VERSION 5.7 ;
BUSBITCHARS "[]" ;
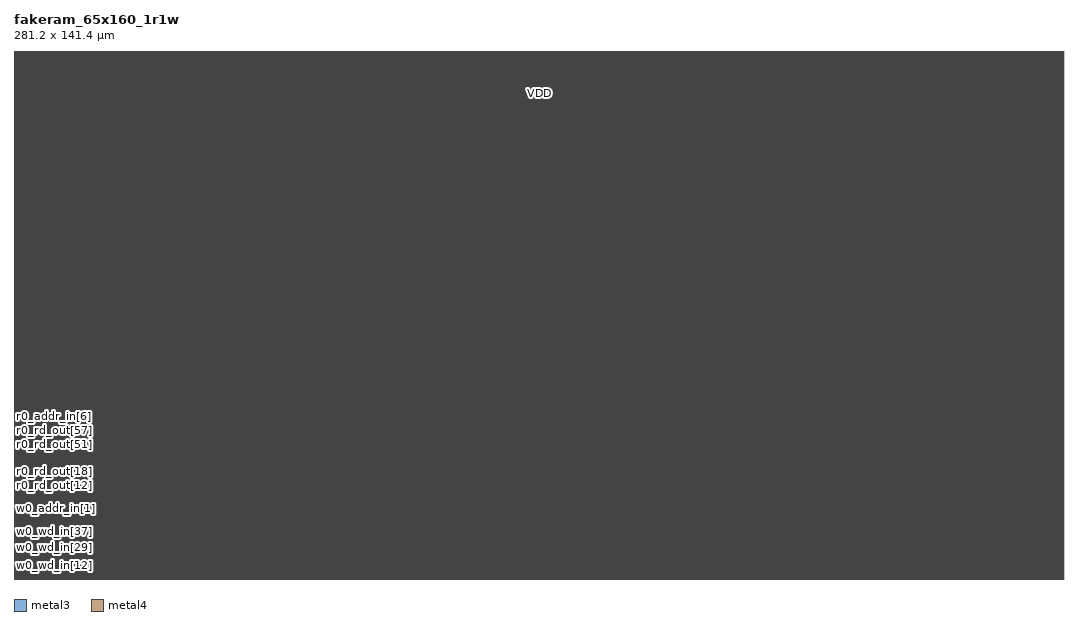
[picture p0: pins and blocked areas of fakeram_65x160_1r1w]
MACRO fakeram_65x160_1r1w
  FOREIGN fakeram_65x160_1r1w 0 0 ;
  SYMMETRY X Y R90 ;
  SIZE 281.200 BY 141.400 ;
  CLASS BLOCK ;
  PIN w0_wd_in[0]
    DIRECTION INPUT ;
    USE SIGNAL ;
    SHAPE ABUTMENT ;
    PORT
      LAYER metal3 ;
      RECT 0.000 0.280 0.140 0.420 ;
    END
  END w0_wd_in[0]
  PIN w0_wd_in[1]
    DIRECTION INPUT ;
    USE SIGNAL ;
    SHAPE ABUTMENT ;
    PORT
      LAYER metal3 ;
      RECT 0.000 0.560 0.140 0.700 ;
    END
  END w0_wd_in[1]
  PIN w0_wd_in[2]
    DIRECTION INPUT ;
    USE SIGNAL ;
    SHAPE ABUTMENT ;
    PORT
      LAYER metal3 ;
      RECT 0.000 0.840 0.140 0.980 ;
    END
  END w0_wd_in[2]
  PIN w0_wd_in[3]
    DIRECTION INPUT ;
    USE SIGNAL ;
    SHAPE ABUTMENT ;
    PORT
      LAYER metal3 ;
      RECT 0.000 1.120 0.140 1.260 ;
    END
  END w0_wd_in[3]
  PIN w0_wd_in[4]
    DIRECTION INPUT ;
    USE SIGNAL ;
    SHAPE ABUTMENT ;
    PORT
      LAYER metal3 ;
      RECT 0.000 1.400 0.140 1.540 ;
    END
  END w0_wd_in[4]
  PIN w0_wd_in[5]
    DIRECTION INPUT ;
    USE SIGNAL ;
    SHAPE ABUTMENT ;
    PORT
      LAYER metal3 ;
      RECT 0.000 1.680 0.140 1.820 ;
    END
  END w0_wd_in[5]
  PIN w0_wd_in[6]
    DIRECTION INPUT ;
    USE SIGNAL ;
    SHAPE ABUTMENT ;
    PORT
      LAYER metal3 ;
      RECT 0.000 1.960 0.140 2.100 ;
    END
  END w0_wd_in[6]
  PIN w0_wd_in[7]
    DIRECTION INPUT ;
    USE SIGNAL ;
    SHAPE ABUTMENT ;
    PORT
      LAYER metal3 ;
      RECT 0.000 2.240 0.140 2.380 ;
    END
  END w0_wd_in[7]
  PIN w0_wd_in[8]
    DIRECTION INPUT ;
    USE SIGNAL ;
    SHAPE ABUTMENT ;
    PORT
      LAYER metal3 ;
      RECT 0.000 2.520 0.140 2.660 ;
    END
  END w0_wd_in[8]
  PIN w0_wd_in[9]
    DIRECTION INPUT ;
    USE SIGNAL ;
    SHAPE ABUTMENT ;
    PORT
      LAYER metal3 ;
      RECT 0.000 2.800 0.140 2.940 ;
    END
  END w0_wd_in[9]
  PIN w0_wd_in[10]
    DIRECTION INPUT ;
    USE SIGNAL ;
    SHAPE ABUTMENT ;
    PORT
      LAYER metal3 ;
      RECT 0.000 3.080 0.140 3.220 ;
    END
  END w0_wd_in[10]
  PIN w0_wd_in[11]
    DIRECTION INPUT ;
    USE SIGNAL ;
    SHAPE ABUTMENT ;
    PORT
      LAYER metal3 ;
      RECT 0.000 3.360 0.140 3.500 ;
    END
  END w0_wd_in[11]
  PIN w0_wd_in[12]
    DIRECTION INPUT ;
    USE SIGNAL ;
    SHAPE ABUTMENT ;
    PORT
      LAYER metal3 ;
      RECT 0.000 3.640 0.140 3.780 ;
    END
  END w0_wd_in[12]
  PIN w0_wd_in[13]
    DIRECTION INPUT ;
    USE SIGNAL ;
    SHAPE ABUTMENT ;
    PORT
      LAYER metal3 ;
      RECT 0.000 3.920 0.140 4.060 ;
    END
  END w0_wd_in[13]
  PIN w0_wd_in[14]
    DIRECTION INPUT ;
    USE SIGNAL ;
    SHAPE ABUTMENT ;
    PORT
      LAYER metal3 ;
      RECT 0.000 4.200 0.140 4.340 ;
    END
  END w0_wd_in[14]
  PIN w0_wd_in[15]
    DIRECTION INPUT ;
    USE SIGNAL ;
    SHAPE ABUTMENT ;
    PORT
      LAYER metal3 ;
      RECT 0.000 4.480 0.140 4.620 ;
    END
  END w0_wd_in[15]
  PIN w0_wd_in[16]
    DIRECTION INPUT ;
    USE SIGNAL ;
    SHAPE ABUTMENT ;
    PORT
      LAYER metal3 ;
      RECT 0.000 4.760 0.140 4.900 ;
    END
  END w0_wd_in[16]
  PIN w0_wd_in[17]
    DIRECTION INPUT ;
    USE SIGNAL ;
    SHAPE ABUTMENT ;
    PORT
      LAYER metal3 ;
      RECT 0.000 5.040 0.140 5.180 ;
    END
  END w0_wd_in[17]
  PIN w0_wd_in[18]
    DIRECTION INPUT ;
    USE SIGNAL ;
    SHAPE ABUTMENT ;
    PORT
      LAYER metal3 ;
      RECT 0.000 5.320 0.140 5.460 ;
    END
  END w0_wd_in[18]
  PIN w0_wd_in[19]
    DIRECTION INPUT ;
    USE SIGNAL ;
    SHAPE ABUTMENT ;
    PORT
      LAYER metal3 ;
      RECT 0.000 5.600 0.140 5.740 ;
    END
  END w0_wd_in[19]
  PIN w0_wd_in[20]
    DIRECTION INPUT ;
    USE SIGNAL ;
    SHAPE ABUTMENT ;
    PORT
      LAYER metal3 ;
      RECT 0.000 5.880 0.140 6.020 ;
    END
  END w0_wd_in[20]
  PIN w0_wd_in[21]
    DIRECTION INPUT ;
    USE SIGNAL ;
    SHAPE ABUTMENT ;
    PORT
      LAYER metal3 ;
      RECT 0.000 6.160 0.140 6.300 ;
    END
  END w0_wd_in[21]
  PIN w0_wd_in[22]
    DIRECTION INPUT ;
    USE SIGNAL ;
    SHAPE ABUTMENT ;
    PORT
      LAYER metal3 ;
      RECT 0.000 6.440 0.140 6.580 ;
    END
  END w0_wd_in[22]
  PIN w0_wd_in[23]
    DIRECTION INPUT ;
    USE SIGNAL ;
    SHAPE ABUTMENT ;
    PORT
      LAYER metal3 ;
      RECT 0.000 6.720 0.140 6.860 ;
    END
  END w0_wd_in[23]
  PIN w0_wd_in[24]
    DIRECTION INPUT ;
    USE SIGNAL ;
    SHAPE ABUTMENT ;
    PORT
      LAYER metal3 ;
      RECT 0.000 7.000 0.140 7.140 ;
    END
  END w0_wd_in[24]
  PIN w0_wd_in[25]
    DIRECTION INPUT ;
    USE SIGNAL ;
    SHAPE ABUTMENT ;
    PORT
      LAYER metal3 ;
      RECT 0.000 7.280 0.140 7.420 ;
    END
  END w0_wd_in[25]
  PIN w0_wd_in[26]
    DIRECTION INPUT ;
    USE SIGNAL ;
    SHAPE ABUTMENT ;
    PORT
      LAYER metal3 ;
      RECT 0.000 7.560 0.140 7.700 ;
    END
  END w0_wd_in[26]
  PIN w0_wd_in[27]
    DIRECTION INPUT ;
    USE SIGNAL ;
    SHAPE ABUTMENT ;
    PORT
      LAYER metal3 ;
      RECT 0.000 7.840 0.140 7.980 ;
    END
  END w0_wd_in[27]
  PIN w0_wd_in[28]
    DIRECTION INPUT ;
    USE SIGNAL ;
    SHAPE ABUTMENT ;
    PORT
      LAYER metal3 ;
      RECT 0.000 8.120 0.140 8.260 ;
    END
  END w0_wd_in[28]
  PIN w0_wd_in[29]
    DIRECTION INPUT ;
    USE SIGNAL ;
    SHAPE ABUTMENT ;
    PORT
      LAYER metal3 ;
      RECT 0.000 8.400 0.140 8.540 ;
    END
  END w0_wd_in[29]
  PIN w0_wd_in[30]
    DIRECTION INPUT ;
    USE SIGNAL ;
    SHAPE ABUTMENT ;
    PORT
      LAYER metal3 ;
      RECT 0.000 8.680 0.140 8.820 ;
    END
  END w0_wd_in[30]
  PIN w0_wd_in[31]
    DIRECTION INPUT ;
    USE SIGNAL ;
    SHAPE ABUTMENT ;
    PORT
      LAYER metal3 ;
      RECT 0.000 8.960 0.140 9.100 ;
    END
  END w0_wd_in[31]
  PIN w0_wd_in[32]
    DIRECTION INPUT ;
    USE SIGNAL ;
    SHAPE ABUTMENT ;
    PORT
      LAYER metal3 ;
      RECT 0.000 9.240 0.140 9.380 ;
    END
  END w0_wd_in[32]
  PIN w0_wd_in[33]
    DIRECTION INPUT ;
    USE SIGNAL ;
    SHAPE ABUTMENT ;
    PORT
      LAYER metal3 ;
      RECT 0.000 9.520 0.140 9.660 ;
    END
  END w0_wd_in[33]
  PIN w0_wd_in[34]
    DIRECTION INPUT ;
    USE SIGNAL ;
    SHAPE ABUTMENT ;
    PORT
      LAYER metal3 ;
      RECT 0.000 9.800 0.140 9.940 ;
    END
  END w0_wd_in[34]
  PIN w0_wd_in[35]
    DIRECTION INPUT ;
    USE SIGNAL ;
    SHAPE ABUTMENT ;
    PORT
      LAYER metal3 ;
      RECT 0.000 10.080 0.140 10.220 ;
    END
  END w0_wd_in[35]
  PIN w0_wd_in[36]
    DIRECTION INPUT ;
    USE SIGNAL ;
    SHAPE ABUTMENT ;
    PORT
      LAYER metal3 ;
      RECT 0.000 10.360 0.140 10.500 ;
    END
  END w0_wd_in[36]
  PIN w0_wd_in[37]
    DIRECTION INPUT ;
    USE SIGNAL ;
    SHAPE ABUTMENT ;
    PORT
      LAYER metal3 ;
      RECT 0.000 10.640 0.140 10.780 ;
    END
  END w0_wd_in[37]
  PIN w0_wd_in[38]
    DIRECTION INPUT ;
    USE SIGNAL ;
    SHAPE ABUTMENT ;
    PORT
      LAYER metal3 ;
      RECT 0.000 10.920 0.140 11.060 ;
    END
  END w0_wd_in[38]
  PIN w0_wd_in[39]
    DIRECTION INPUT ;
    USE SIGNAL ;
    SHAPE ABUTMENT ;
    PORT
      LAYER metal3 ;
      RECT 0.000 11.200 0.140 11.340 ;
    END
  END w0_wd_in[39]
  PIN w0_wd_in[40]
    DIRECTION INPUT ;
    USE SIGNAL ;
    SHAPE ABUTMENT ;
    PORT
      LAYER metal3 ;
      RECT 0.000 11.480 0.140 11.620 ;
    END
  END w0_wd_in[40]
  PIN w0_wd_in[41]
    DIRECTION INPUT ;
    USE SIGNAL ;
    SHAPE ABUTMENT ;
    PORT
      LAYER metal3 ;
      RECT 0.000 11.760 0.140 11.900 ;
    END
  END w0_wd_in[41]
  PIN w0_wd_in[42]
    DIRECTION INPUT ;
    USE SIGNAL ;
    SHAPE ABUTMENT ;
    PORT
      LAYER metal3 ;
      RECT 0.000 12.040 0.140 12.180 ;
    END
  END w0_wd_in[42]
  PIN w0_wd_in[43]
    DIRECTION INPUT ;
    USE SIGNAL ;
    SHAPE ABUTMENT ;
    PORT
      LAYER metal3 ;
      RECT 0.000 12.320 0.140 12.460 ;
    END
  END w0_wd_in[43]
  PIN w0_wd_in[44]
    DIRECTION INPUT ;
    USE SIGNAL ;
    SHAPE ABUTMENT ;
    PORT
      LAYER metal3 ;
      RECT 0.000 12.600 0.140 12.740 ;
    END
  END w0_wd_in[44]
  PIN w0_wd_in[45]
    DIRECTION INPUT ;
    USE SIGNAL ;
    SHAPE ABUTMENT ;
    PORT
      LAYER metal3 ;
      RECT 0.000 12.880 0.140 13.020 ;
    END
  END w0_wd_in[45]
  PIN w0_wd_in[46]
    DIRECTION INPUT ;
    USE SIGNAL ;
    SHAPE ABUTMENT ;
    PORT
      LAYER metal3 ;
      RECT 0.000 13.160 0.140 13.300 ;
    END
  END w0_wd_in[46]
  PIN w0_wd_in[47]
    DIRECTION INPUT ;
    USE SIGNAL ;
    SHAPE ABUTMENT ;
    PORT
      LAYER metal3 ;
      RECT 0.000 13.440 0.140 13.580 ;
    END
  END w0_wd_in[47]
  PIN w0_wd_in[48]
    DIRECTION INPUT ;
    USE SIGNAL ;
    SHAPE ABUTMENT ;
    PORT
      LAYER metal3 ;
      RECT 0.000 13.720 0.140 13.860 ;
    END
  END w0_wd_in[48]
  PIN w0_wd_in[49]
    DIRECTION INPUT ;
    USE SIGNAL ;
    SHAPE ABUTMENT ;
    PORT
      LAYER metal3 ;
      RECT 0.000 14.000 0.140 14.140 ;
    END
  END w0_wd_in[49]
  PIN w0_wd_in[50]
    DIRECTION INPUT ;
    USE SIGNAL ;
    SHAPE ABUTMENT ;
    PORT
      LAYER metal3 ;
      RECT 0.000 14.280 0.140 14.420 ;
    END
  END w0_wd_in[50]
  PIN w0_wd_in[51]
    DIRECTION INPUT ;
    USE SIGNAL ;
    SHAPE ABUTMENT ;
    PORT
      LAYER metal3 ;
      RECT 0.000 14.560 0.140 14.700 ;
    END
  END w0_wd_in[51]
  PIN w0_wd_in[52]
    DIRECTION INPUT ;
    USE SIGNAL ;
    SHAPE ABUTMENT ;
    PORT
      LAYER metal3 ;
      RECT 0.000 14.840 0.140 14.980 ;
    END
  END w0_wd_in[52]
  PIN w0_wd_in[53]
    DIRECTION INPUT ;
    USE SIGNAL ;
    SHAPE ABUTMENT ;
    PORT
      LAYER metal3 ;
      RECT 0.000 15.120 0.140 15.260 ;
    END
  END w0_wd_in[53]
  PIN w0_wd_in[54]
    DIRECTION INPUT ;
    USE SIGNAL ;
    SHAPE ABUTMENT ;
    PORT
      LAYER metal3 ;
      RECT 0.000 15.400 0.140 15.540 ;
    END
  END w0_wd_in[54]
  PIN w0_wd_in[55]
    DIRECTION INPUT ;
    USE SIGNAL ;
    SHAPE ABUTMENT ;
    PORT
      LAYER metal3 ;
      RECT 0.000 15.680 0.140 15.820 ;
    END
  END w0_wd_in[55]
  PIN w0_wd_in[56]
    DIRECTION INPUT ;
    USE SIGNAL ;
    SHAPE ABUTMENT ;
    PORT
      LAYER metal3 ;
      RECT 0.000 15.960 0.140 16.100 ;
    END
  END w0_wd_in[56]
  PIN w0_wd_in[57]
    DIRECTION INPUT ;
    USE SIGNAL ;
    SHAPE ABUTMENT ;
    PORT
      LAYER metal3 ;
      RECT 0.000 16.240 0.140 16.380 ;
    END
  END w0_wd_in[57]
  PIN w0_wd_in[58]
    DIRECTION INPUT ;
    USE SIGNAL ;
    SHAPE ABUTMENT ;
    PORT
      LAYER metal3 ;
      RECT 0.000 16.520 0.140 16.660 ;
    END
  END w0_wd_in[58]
  PIN w0_wd_in[59]
    DIRECTION INPUT ;
    USE SIGNAL ;
    SHAPE ABUTMENT ;
    PORT
      LAYER metal3 ;
      RECT 0.000 16.800 0.140 16.940 ;
    END
  END w0_wd_in[59]
  PIN w0_wd_in[60]
    DIRECTION INPUT ;
    USE SIGNAL ;
    SHAPE ABUTMENT ;
    PORT
      LAYER metal3 ;
      RECT 0.000 17.080 0.140 17.220 ;
    END
  END w0_wd_in[60]
  PIN w0_wd_in[61]
    DIRECTION INPUT ;
    USE SIGNAL ;
    SHAPE ABUTMENT ;
    PORT
      LAYER metal3 ;
      RECT 0.000 17.360 0.140 17.500 ;
    END
  END w0_wd_in[61]
  PIN w0_wd_in[62]
    DIRECTION INPUT ;
    USE SIGNAL ;
    SHAPE ABUTMENT ;
    PORT
      LAYER metal3 ;
      RECT 0.000 17.640 0.140 17.780 ;
    END
  END w0_wd_in[62]
  PIN w0_wd_in[63]
    DIRECTION INPUT ;
    USE SIGNAL ;
    SHAPE ABUTMENT ;
    PORT
      LAYER metal3 ;
      RECT 0.000 17.920 0.140 18.060 ;
    END
  END w0_wd_in[63]
  PIN w0_wd_in[64]
    DIRECTION INPUT ;
    USE SIGNAL ;
    SHAPE ABUTMENT ;
    PORT
      LAYER metal3 ;
      RECT 0.000 18.200 0.140 18.340 ;
    END
  END w0_wd_in[64]
  PIN w0_addr_in[0]
    DIRECTION INPUT ;
    USE SIGNAL ;
    SHAPE ABUTMENT ;
    PORT
      LAYER metal3 ;
      RECT 0.000 18.480 0.140 18.620 ;
    END
  END w0_addr_in[0]
  PIN w0_addr_in[1]
    DIRECTION INPUT ;
    USE SIGNAL ;
    SHAPE ABUTMENT ;
    PORT
      LAYER metal3 ;
      RECT 0.000 18.760 0.140 18.900 ;
    END
  END w0_addr_in[1]
  PIN w0_addr_in[2]
    DIRECTION INPUT ;
    USE SIGNAL ;
    SHAPE ABUTMENT ;
    PORT
      LAYER metal3 ;
      RECT 0.000 19.040 0.140 19.180 ;
    END
  END w0_addr_in[2]
  PIN w0_addr_in[3]
    DIRECTION INPUT ;
    USE SIGNAL ;
    SHAPE ABUTMENT ;
    PORT
      LAYER metal3 ;
      RECT 0.000 19.320 0.140 19.460 ;
    END
  END w0_addr_in[3]
  PIN w0_addr_in[4]
    DIRECTION INPUT ;
    USE SIGNAL ;
    SHAPE ABUTMENT ;
    PORT
      LAYER metal3 ;
      RECT 0.000 19.600 0.140 19.740 ;
    END
  END w0_addr_in[4]
  PIN w0_addr_in[5]
    DIRECTION INPUT ;
    USE SIGNAL ;
    SHAPE ABUTMENT ;
    PORT
      LAYER metal3 ;
      RECT 0.000 19.880 0.140 20.020 ;
    END
  END w0_addr_in[5]
  PIN w0_addr_in[6]
    DIRECTION INPUT ;
    USE SIGNAL ;
    SHAPE ABUTMENT ;
    PORT
      LAYER metal3 ;
      RECT 0.000 20.160 0.140 20.300 ;
    END
  END w0_addr_in[6]
  PIN w0_addr_in[7]
    DIRECTION INPUT ;
    USE SIGNAL ;
    SHAPE ABUTMENT ;
    PORT
      LAYER metal3 ;
      RECT 0.000 20.440 0.140 20.580 ;
    END
  END w0_addr_in[7]
  PIN w0_clk
    DIRECTION INPUT ;
    USE SIGNAL ;
    SHAPE ABUTMENT ;
    PORT
      LAYER metal3 ;
      RECT 0.000 20.720 0.140 20.860 ;
    END
  END w0_clk
  PIN w0_ce_in
    DIRECTION INPUT ;
    USE SIGNAL ;
    SHAPE ABUTMENT ;
    PORT
      LAYER metal3 ;
      RECT 0.000 21.000 0.140 21.140 ;
    END
  END w0_ce_in
  PIN w0_we_in
    DIRECTION INPUT ;
    USE SIGNAL ;
    SHAPE ABUTMENT ;
    PORT
      LAYER metal3 ;
      RECT 0.000 21.280 0.140 21.420 ;
    END
  END w0_we_in
  PIN r0_rd_out[0]
    DIRECTION OUTPUT ;
    USE SIGNAL ;
    SHAPE ABUTMENT ;
    PORT
      LAYER metal3 ;
      RECT 0.000 21.560 0.140 21.700 ;
    END
  END r0_rd_out[0]
  PIN r0_rd_out[1]
    DIRECTION OUTPUT ;
    USE SIGNAL ;
    SHAPE ABUTMENT ;
    PORT
      LAYER metal3 ;
      RECT 0.000 21.840 0.140 21.980 ;
    END
  END r0_rd_out[1]
  PIN r0_rd_out[2]
    DIRECTION OUTPUT ;
    USE SIGNAL ;
    SHAPE ABUTMENT ;
    PORT
      LAYER metal3 ;
      RECT 0.000 22.120 0.140 22.260 ;
    END
  END r0_rd_out[2]
  PIN r0_rd_out[3]
    DIRECTION OUTPUT ;
    USE SIGNAL ;
    SHAPE ABUTMENT ;
    PORT
      LAYER metal3 ;
      RECT 0.000 22.400 0.140 22.540 ;
    END
  END r0_rd_out[3]
  PIN r0_rd_out[4]
    DIRECTION OUTPUT ;
    USE SIGNAL ;
    SHAPE ABUTMENT ;
    PORT
      LAYER metal3 ;
      RECT 0.000 22.680 0.140 22.820 ;
    END
  END r0_rd_out[4]
  PIN r0_rd_out[5]
    DIRECTION OUTPUT ;
    USE SIGNAL ;
    SHAPE ABUTMENT ;
    PORT
      LAYER metal3 ;
      RECT 0.000 22.960 0.140 23.100 ;
    END
  END r0_rd_out[5]
  PIN r0_rd_out[6]
    DIRECTION OUTPUT ;
    USE SIGNAL ;
    SHAPE ABUTMENT ;
    PORT
      LAYER metal3 ;
      RECT 0.000 23.240 0.140 23.380 ;
    END
  END r0_rd_out[6]
  PIN r0_rd_out[7]
    DIRECTION OUTPUT ;
    USE SIGNAL ;
    SHAPE ABUTMENT ;
    PORT
      LAYER metal3 ;
      RECT 0.000 23.520 0.140 23.660 ;
    END
  END r0_rd_out[7]
  PIN r0_rd_out[8]
    DIRECTION OUTPUT ;
    USE SIGNAL ;
    SHAPE ABUTMENT ;
    PORT
      LAYER metal3 ;
      RECT 0.000 23.800 0.140 23.940 ;
    END
  END r0_rd_out[8]
  PIN r0_rd_out[9]
    DIRECTION OUTPUT ;
    USE SIGNAL ;
    SHAPE ABUTMENT ;
    PORT
      LAYER metal3 ;
      RECT 0.000 24.080 0.140 24.220 ;
    END
  END r0_rd_out[9]
  PIN r0_rd_out[10]
    DIRECTION OUTPUT ;
    USE SIGNAL ;
    SHAPE ABUTMENT ;
    PORT
      LAYER metal3 ;
      RECT 0.000 24.360 0.140 24.500 ;
    END
  END r0_rd_out[10]
  PIN r0_rd_out[11]
    DIRECTION OUTPUT ;
    USE SIGNAL ;
    SHAPE ABUTMENT ;
    PORT
      LAYER metal3 ;
      RECT 0.000 24.640 0.140 24.780 ;
    END
  END r0_rd_out[11]
  PIN r0_rd_out[12]
    DIRECTION OUTPUT ;
    USE SIGNAL ;
    SHAPE ABUTMENT ;
    PORT
      LAYER metal3 ;
      RECT 0.000 24.920 0.140 25.060 ;
    END
  END r0_rd_out[12]
  PIN r0_rd_out[13]
    DIRECTION OUTPUT ;
    USE SIGNAL ;
    SHAPE ABUTMENT ;
    PORT
      LAYER metal3 ;
      RECT 0.000 25.200 0.140 25.340 ;
    END
  END r0_rd_out[13]
  PIN r0_rd_out[14]
    DIRECTION OUTPUT ;
    USE SIGNAL ;
    SHAPE ABUTMENT ;
    PORT
      LAYER metal3 ;
      RECT 0.000 25.480 0.140 25.620 ;
    END
  END r0_rd_out[14]
  PIN r0_rd_out[15]
    DIRECTION OUTPUT ;
    USE SIGNAL ;
    SHAPE ABUTMENT ;
    PORT
      LAYER metal3 ;
      RECT 0.000 25.760 0.140 25.900 ;
    END
  END r0_rd_out[15]
  PIN r0_rd_out[16]
    DIRECTION OUTPUT ;
    USE SIGNAL ;
    SHAPE ABUTMENT ;
    PORT
      LAYER metal3 ;
      RECT 0.000 26.040 0.140 26.180 ;
    END
  END r0_rd_out[16]
  PIN r0_rd_out[17]
    DIRECTION OUTPUT ;
    USE SIGNAL ;
    SHAPE ABUTMENT ;
    PORT
      LAYER metal3 ;
      RECT 0.000 26.320 0.140 26.460 ;
    END
  END r0_rd_out[17]
  PIN r0_rd_out[18]
    DIRECTION OUTPUT ;
    USE SIGNAL ;
    SHAPE ABUTMENT ;
    PORT
      LAYER metal3 ;
      RECT 0.000 26.600 0.140 26.740 ;
    END
  END r0_rd_out[18]
  PIN r0_rd_out[19]
    DIRECTION OUTPUT ;
    USE SIGNAL ;
    SHAPE ABUTMENT ;
    PORT
      LAYER metal3 ;
      RECT 0.000 26.880 0.140 27.020 ;
    END
  END r0_rd_out[19]
  PIN r0_rd_out[20]
    DIRECTION OUTPUT ;
    USE SIGNAL ;
    SHAPE ABUTMENT ;
    PORT
      LAYER metal3 ;
      RECT 0.000 27.160 0.140 27.300 ;
    END
  END r0_rd_out[20]
  PIN r0_rd_out[21]
    DIRECTION OUTPUT ;
    USE SIGNAL ;
    SHAPE ABUTMENT ;
    PORT
      LAYER metal3 ;
      RECT 0.000 27.440 0.140 27.580 ;
    END
  END r0_rd_out[21]
  PIN r0_rd_out[22]
    DIRECTION OUTPUT ;
    USE SIGNAL ;
    SHAPE ABUTMENT ;
    PORT
      LAYER metal3 ;
      RECT 0.000 27.720 0.140 27.860 ;
    END
  END r0_rd_out[22]
  PIN r0_rd_out[23]
    DIRECTION OUTPUT ;
    USE SIGNAL ;
    SHAPE ABUTMENT ;
    PORT
      LAYER metal3 ;
      RECT 0.000 28.000 0.140 28.140 ;
    END
  END r0_rd_out[23]
  PIN r0_rd_out[24]
    DIRECTION OUTPUT ;
    USE SIGNAL ;
    SHAPE ABUTMENT ;
    PORT
      LAYER metal3 ;
      RECT 0.000 28.280 0.140 28.420 ;
    END
  END r0_rd_out[24]
  PIN r0_rd_out[25]
    DIRECTION OUTPUT ;
    USE SIGNAL ;
    SHAPE ABUTMENT ;
    PORT
      LAYER metal3 ;
      RECT 0.000 28.560 0.140 28.700 ;
    END
  END r0_rd_out[25]
  PIN r0_rd_out[26]
    DIRECTION OUTPUT ;
    USE SIGNAL ;
    SHAPE ABUTMENT ;
    PORT
      LAYER metal3 ;
      RECT 0.000 28.840 0.140 28.980 ;
    END
  END r0_rd_out[26]
  PIN r0_rd_out[27]
    DIRECTION OUTPUT ;
    USE SIGNAL ;
    SHAPE ABUTMENT ;
    PORT
      LAYER metal3 ;
      RECT 0.000 29.120 0.140 29.260 ;
    END
  END r0_rd_out[27]
  PIN r0_rd_out[28]
    DIRECTION OUTPUT ;
    USE SIGNAL ;
    SHAPE ABUTMENT ;
    PORT
      LAYER metal3 ;
      RECT 0.000 29.400 0.140 29.540 ;
    END
  END r0_rd_out[28]
  PIN r0_rd_out[29]
    DIRECTION OUTPUT ;
    USE SIGNAL ;
    SHAPE ABUTMENT ;
    PORT
      LAYER metal3 ;
      RECT 0.000 29.680 0.140 29.820 ;
    END
  END r0_rd_out[29]
  PIN r0_rd_out[30]
    DIRECTION OUTPUT ;
    USE SIGNAL ;
    SHAPE ABUTMENT ;
    PORT
      LAYER metal3 ;
      RECT 0.000 29.960 0.140 30.100 ;
    END
  END r0_rd_out[30]
  PIN r0_rd_out[31]
    DIRECTION OUTPUT ;
    USE SIGNAL ;
    SHAPE ABUTMENT ;
    PORT
      LAYER metal3 ;
      RECT 0.000 30.240 0.140 30.380 ;
    END
  END r0_rd_out[31]
  PIN r0_rd_out[32]
    DIRECTION OUTPUT ;
    USE SIGNAL ;
    SHAPE ABUTMENT ;
    PORT
      LAYER metal3 ;
      RECT 0.000 30.520 0.140 30.660 ;
    END
  END r0_rd_out[32]
  PIN r0_rd_out[33]
    DIRECTION OUTPUT ;
    USE SIGNAL ;
    SHAPE ABUTMENT ;
    PORT
      LAYER metal3 ;
      RECT 0.000 30.800 0.140 30.940 ;
    END
  END r0_rd_out[33]
  PIN r0_rd_out[34]
    DIRECTION OUTPUT ;
    USE SIGNAL ;
    SHAPE ABUTMENT ;
    PORT
      LAYER metal3 ;
      RECT 0.000 31.080 0.140 31.220 ;
    END
  END r0_rd_out[34]
  PIN r0_rd_out[35]
    DIRECTION OUTPUT ;
    USE SIGNAL ;
    SHAPE ABUTMENT ;
    PORT
      LAYER metal3 ;
      RECT 0.000 31.360 0.140 31.500 ;
    END
  END r0_rd_out[35]
  PIN r0_rd_out[36]
    DIRECTION OUTPUT ;
    USE SIGNAL ;
    SHAPE ABUTMENT ;
    PORT
      LAYER metal3 ;
      RECT 0.000 31.640 0.140 31.780 ;
    END
  END r0_rd_out[36]
  PIN r0_rd_out[37]
    DIRECTION OUTPUT ;
    USE SIGNAL ;
    SHAPE ABUTMENT ;
    PORT
      LAYER metal3 ;
      RECT 0.000 31.920 0.140 32.060 ;
    END
  END r0_rd_out[37]
  PIN r0_rd_out[38]
    DIRECTION OUTPUT ;
    USE SIGNAL ;
    SHAPE ABUTMENT ;
    PORT
      LAYER metal3 ;
      RECT 0.000 32.200 0.140 32.340 ;
    END
  END r0_rd_out[38]
  PIN r0_rd_out[39]
    DIRECTION OUTPUT ;
    USE SIGNAL ;
    SHAPE ABUTMENT ;
    PORT
      LAYER metal3 ;
      RECT 0.000 32.480 0.140 32.620 ;
    END
  END r0_rd_out[39]
  PIN r0_rd_out[40]
    DIRECTION OUTPUT ;
    USE SIGNAL ;
    SHAPE ABUTMENT ;
    PORT
      LAYER metal3 ;
      RECT 0.000 32.760 0.140 32.900 ;
    END
  END r0_rd_out[40]
  PIN r0_rd_out[41]
    DIRECTION OUTPUT ;
    USE SIGNAL ;
    SHAPE ABUTMENT ;
    PORT
      LAYER metal3 ;
      RECT 0.000 33.040 0.140 33.180 ;
    END
  END r0_rd_out[41]
  PIN r0_rd_out[42]
    DIRECTION OUTPUT ;
    USE SIGNAL ;
    SHAPE ABUTMENT ;
    PORT
      LAYER metal3 ;
      RECT 0.000 33.320 0.140 33.460 ;
    END
  END r0_rd_out[42]
  PIN r0_rd_out[43]
    DIRECTION OUTPUT ;
    USE SIGNAL ;
    SHAPE ABUTMENT ;
    PORT
      LAYER metal3 ;
      RECT 0.000 33.600 0.140 33.740 ;
    END
  END r0_rd_out[43]
  PIN r0_rd_out[44]
    DIRECTION OUTPUT ;
    USE SIGNAL ;
    SHAPE ABUTMENT ;
    PORT
      LAYER metal3 ;
      RECT 0.000 33.880 0.140 34.020 ;
    END
  END r0_rd_out[44]
  PIN r0_rd_out[45]
    DIRECTION OUTPUT ;
    USE SIGNAL ;
    SHAPE ABUTMENT ;
    PORT
      LAYER metal3 ;
      RECT 0.000 34.160 0.140 34.300 ;
    END
  END r0_rd_out[45]
  PIN r0_rd_out[46]
    DIRECTION OUTPUT ;
    USE SIGNAL ;
    SHAPE ABUTMENT ;
    PORT
      LAYER metal3 ;
      RECT 0.000 34.440 0.140 34.580 ;
    END
  END r0_rd_out[46]
  PIN r0_rd_out[47]
    DIRECTION OUTPUT ;
    USE SIGNAL ;
    SHAPE ABUTMENT ;
    PORT
      LAYER metal3 ;
      RECT 0.000 34.720 0.140 34.860 ;
    END
  END r0_rd_out[47]
  PIN r0_rd_out[48]
    DIRECTION OUTPUT ;
    USE SIGNAL ;
    SHAPE ABUTMENT ;
    PORT
      LAYER metal3 ;
      RECT 0.000 35.000 0.140 35.140 ;
    END
  END r0_rd_out[48]
  PIN r0_rd_out[49]
    DIRECTION OUTPUT ;
    USE SIGNAL ;
    SHAPE ABUTMENT ;
    PORT
      LAYER metal3 ;
      RECT 0.000 35.280 0.140 35.420 ;
    END
  END r0_rd_out[49]
  PIN r0_rd_out[50]
    DIRECTION OUTPUT ;
    USE SIGNAL ;
    SHAPE ABUTMENT ;
    PORT
      LAYER metal3 ;
      RECT 0.000 35.560 0.140 35.700 ;
    END
  END r0_rd_out[50]
  PIN r0_rd_out[51]
    DIRECTION OUTPUT ;
    USE SIGNAL ;
    SHAPE ABUTMENT ;
    PORT
      LAYER metal3 ;
      RECT 0.000 35.840 0.140 35.980 ;
    END
  END r0_rd_out[51]
  PIN r0_rd_out[52]
    DIRECTION OUTPUT ;
    USE SIGNAL ;
    SHAPE ABUTMENT ;
    PORT
      LAYER metal3 ;
      RECT 0.000 36.120 0.140 36.260 ;
    END
  END r0_rd_out[52]
  PIN r0_rd_out[53]
    DIRECTION OUTPUT ;
    USE SIGNAL ;
    SHAPE ABUTMENT ;
    PORT
      LAYER metal3 ;
      RECT 0.000 36.400 0.140 36.540 ;
    END
  END r0_rd_out[53]
  PIN r0_rd_out[54]
    DIRECTION OUTPUT ;
    USE SIGNAL ;
    SHAPE ABUTMENT ;
    PORT
      LAYER metal3 ;
      RECT 0.000 36.680 0.140 36.820 ;
    END
  END r0_rd_out[54]
  PIN r0_rd_out[55]
    DIRECTION OUTPUT ;
    USE SIGNAL ;
    SHAPE ABUTMENT ;
    PORT
      LAYER metal3 ;
      RECT 0.000 36.960 0.140 37.100 ;
    END
  END r0_rd_out[55]
  PIN r0_rd_out[56]
    DIRECTION OUTPUT ;
    USE SIGNAL ;
    SHAPE ABUTMENT ;
    PORT
      LAYER metal3 ;
      RECT 0.000 37.240 0.140 37.380 ;
    END
  END r0_rd_out[56]
  PIN r0_rd_out[57]
    DIRECTION OUTPUT ;
    USE SIGNAL ;
    SHAPE ABUTMENT ;
    PORT
      LAYER metal3 ;
      RECT 0.000 37.520 0.140 37.660 ;
    END
  END r0_rd_out[57]
  PIN r0_rd_out[58]
    DIRECTION OUTPUT ;
    USE SIGNAL ;
    SHAPE ABUTMENT ;
    PORT
      LAYER metal3 ;
      RECT 0.000 37.800 0.140 37.940 ;
    END
  END r0_rd_out[58]
  PIN r0_rd_out[59]
    DIRECTION OUTPUT ;
    USE SIGNAL ;
    SHAPE ABUTMENT ;
    PORT
      LAYER metal3 ;
      RECT 0.000 38.080 0.140 38.220 ;
    END
  END r0_rd_out[59]
  PIN r0_rd_out[60]
    DIRECTION OUTPUT ;
    USE SIGNAL ;
    SHAPE ABUTMENT ;
    PORT
      LAYER metal3 ;
      RECT 0.000 38.360 0.140 38.500 ;
    END
  END r0_rd_out[60]
  PIN r0_rd_out[61]
    DIRECTION OUTPUT ;
    USE SIGNAL ;
    SHAPE ABUTMENT ;
    PORT
      LAYER metal3 ;
      RECT 0.000 38.640 0.140 38.780 ;
    END
  END r0_rd_out[61]
  PIN r0_rd_out[62]
    DIRECTION OUTPUT ;
    USE SIGNAL ;
    SHAPE ABUTMENT ;
    PORT
      LAYER metal3 ;
      RECT 0.000 38.920 0.140 39.060 ;
    END
  END r0_rd_out[62]
  PIN r0_rd_out[63]
    DIRECTION OUTPUT ;
    USE SIGNAL ;
    SHAPE ABUTMENT ;
    PORT
      LAYER metal3 ;
      RECT 0.000 39.200 0.140 39.340 ;
    END
  END r0_rd_out[63]
  PIN r0_rd_out[64]
    DIRECTION OUTPUT ;
    USE SIGNAL ;
    SHAPE ABUTMENT ;
    PORT
      LAYER metal3 ;
      RECT 0.000 39.480 0.140 39.620 ;
    END
  END r0_rd_out[64]
  PIN r0_addr_in[0]
    DIRECTION INPUT ;
    USE SIGNAL ;
    SHAPE ABUTMENT ;
    PORT
      LAYER metal3 ;
      RECT 0.000 39.760 0.140 39.900 ;
    END
  END r0_addr_in[0]
  PIN r0_addr_in[1]
    DIRECTION INPUT ;
    USE SIGNAL ;
    SHAPE ABUTMENT ;
    PORT
      LAYER metal3 ;
      RECT 0.000 40.040 0.140 40.180 ;
    END
  END r0_addr_in[1]
  PIN r0_addr_in[2]
    DIRECTION INPUT ;
    USE SIGNAL ;
    SHAPE ABUTMENT ;
    PORT
      LAYER metal3 ;
      RECT 0.000 40.320 0.140 40.460 ;
    END
  END r0_addr_in[2]
  PIN r0_addr_in[3]
    DIRECTION INPUT ;
    USE SIGNAL ;
    SHAPE ABUTMENT ;
    PORT
      LAYER metal3 ;
      RECT 0.000 40.600 0.140 40.740 ;
    END
  END r0_addr_in[3]
  PIN r0_addr_in[4]
    DIRECTION INPUT ;
    USE SIGNAL ;
    SHAPE ABUTMENT ;
    PORT
      LAYER metal3 ;
      RECT 0.000 40.880 0.140 41.020 ;
    END
  END r0_addr_in[4]
  PIN r0_addr_in[5]
    DIRECTION INPUT ;
    USE SIGNAL ;
    SHAPE ABUTMENT ;
    PORT
      LAYER metal3 ;
      RECT 0.000 41.160 0.140 41.300 ;
    END
  END r0_addr_in[5]
  PIN r0_addr_in[6]
    DIRECTION INPUT ;
    USE SIGNAL ;
    SHAPE ABUTMENT ;
    PORT
      LAYER metal3 ;
      RECT 0.000 41.440 0.140 41.580 ;
    END
  END r0_addr_in[6]
  PIN r0_addr_in[7]
    DIRECTION INPUT ;
    USE SIGNAL ;
    SHAPE ABUTMENT ;
    PORT
      LAYER metal3 ;
      RECT 0.000 41.720 0.140 41.860 ;
    END
  END r0_addr_in[7]
  PIN r0_clk
    DIRECTION INPUT ;
    USE SIGNAL ;
    SHAPE ABUTMENT ;
    PORT
      LAYER metal3 ;
      RECT 0.000 42.000 0.140 42.140 ;
    END
  END r0_clk
  PIN r0_ce_in
    DIRECTION INPUT ;
    USE SIGNAL ;
    SHAPE ABUTMENT ;
    PORT
      LAYER metal3 ;
      RECT 0.000 42.280 0.140 42.420 ;
    END
  END r0_ce_in
  PIN VDD
    DIRECTION INOUT ;
    USE POWER ;
    PORT
      LAYER metal4 ;
      RECT 0.190 0.000 281.010 0.140 ;
      RECT 0.190 0.560 281.010 0.700 ;
      RECT 0.190 1.120 281.010 1.260 ;
      RECT 0.190 1.680 281.010 1.820 ;
      RECT 0.190 2.240 281.010 2.380 ;
      RECT 0.190 2.800 281.010 2.940 ;
      RECT 0.190 3.360 281.010 3.500 ;
      RECT 0.190 3.920 281.010 4.060 ;
      RECT 0.190 4.480 281.010 4.620 ;
      RECT 0.190 5.040 281.010 5.180 ;
      RECT 0.190 5.600 281.010 5.740 ;
      RECT 0.190 6.160 281.010 6.300 ;
      RECT 0.190 6.720 281.010 6.860 ;
      RECT 0.190 7.280 281.010 7.420 ;
      RECT 0.190 7.840 281.010 7.980 ;
      RECT 0.190 8.400 281.010 8.540 ;
      RECT 0.190 8.960 281.010 9.100 ;
      RECT 0.190 9.520 281.010 9.660 ;
      RECT 0.190 10.080 281.010 10.220 ;
      RECT 0.190 10.640 281.010 10.780 ;
      RECT 0.190 11.200 281.010 11.340 ;
      RECT 0.190 11.760 281.010 11.900 ;
      RECT 0.190 12.320 281.010 12.460 ;
      RECT 0.190 12.880 281.010 13.020 ;
      RECT 0.190 13.440 281.010 13.580 ;
      RECT 0.190 14.000 281.010 14.140 ;
      RECT 0.190 14.560 281.010 14.700 ;
      RECT 0.190 15.120 281.010 15.260 ;
      RECT 0.190 15.680 281.010 15.820 ;
      RECT 0.190 16.240 281.010 16.380 ;
      RECT 0.190 16.800 281.010 16.940 ;
      RECT 0.190 17.360 281.010 17.500 ;
      RECT 0.190 17.920 281.010 18.060 ;
      RECT 0.190 18.480 281.010 18.620 ;
      RECT 0.190 19.040 281.010 19.180 ;
      RECT 0.190 19.600 281.010 19.740 ;
      RECT 0.190 20.160 281.010 20.300 ;
      RECT 0.190 20.720 281.010 20.860 ;
      RECT 0.190 21.280 281.010 21.420 ;
      RECT 0.190 21.840 281.010 21.980 ;
      RECT 0.190 22.400 281.010 22.540 ;
      RECT 0.190 22.960 281.010 23.100 ;
      RECT 0.190 23.520 281.010 23.660 ;
      RECT 0.190 24.080 281.010 24.220 ;
      RECT 0.190 24.640 281.010 24.780 ;
      RECT 0.190 25.200 281.010 25.340 ;
      RECT 0.190 25.760 281.010 25.900 ;
      RECT 0.190 26.320 281.010 26.460 ;
      RECT 0.190 26.880 281.010 27.020 ;
      RECT 0.190 27.440 281.010 27.580 ;
      RECT 0.190 28.000 281.010 28.140 ;
      RECT 0.190 28.560 281.010 28.700 ;
      RECT 0.190 29.120 281.010 29.260 ;
      RECT 0.190 29.680 281.010 29.820 ;
      RECT 0.190 30.240 281.010 30.380 ;
      RECT 0.190 30.800 281.010 30.940 ;
      RECT 0.190 31.360 281.010 31.500 ;
      RECT 0.190 31.920 281.010 32.060 ;
      RECT 0.190 32.480 281.010 32.620 ;
      RECT 0.190 33.040 281.010 33.180 ;
      RECT 0.190 33.600 281.010 33.740 ;
      RECT 0.190 34.160 281.010 34.300 ;
      RECT 0.190 34.720 281.010 34.860 ;
      RECT 0.190 35.280 281.010 35.420 ;
      RECT 0.190 35.840 281.010 35.980 ;
      RECT 0.190 36.400 281.010 36.540 ;
      RECT 0.190 36.960 281.010 37.100 ;
      RECT 0.190 37.520 281.010 37.660 ;
      RECT 0.190 38.080 281.010 38.220 ;
      RECT 0.190 38.640 281.010 38.780 ;
      RECT 0.190 39.200 281.010 39.340 ;
      RECT 0.190 39.760 281.010 39.900 ;
      RECT 0.190 40.320 281.010 40.460 ;
      RECT 0.190 40.880 281.010 41.020 ;
      RECT 0.190 41.440 281.010 41.580 ;
      RECT 0.190 42.000 281.010 42.140 ;
      RECT 0.190 42.560 281.010 42.700 ;
      RECT 0.190 43.120 281.010 43.260 ;
      RECT 0.190 43.680 281.010 43.820 ;
      RECT 0.190 44.240 281.010 44.380 ;
      RECT 0.190 44.800 281.010 44.940 ;
      RECT 0.190 45.360 281.010 45.500 ;
      RECT 0.190 45.920 281.010 46.060 ;
      RECT 0.190 46.480 281.010 46.620 ;
      RECT 0.190 47.040 281.010 47.180 ;
      RECT 0.190 47.600 281.010 47.740 ;
      RECT 0.190 48.160 281.010 48.300 ;
      RECT 0.190 48.720 281.010 48.860 ;
      RECT 0.190 49.280 281.010 49.420 ;
      RECT 0.190 49.840 281.010 49.980 ;
      RECT 0.190 50.400 281.010 50.540 ;
      RECT 0.190 50.960 281.010 51.100 ;
      RECT 0.190 51.520 281.010 51.660 ;
      RECT 0.190 52.080 281.010 52.220 ;
      RECT 0.190 52.640 281.010 52.780 ;
      RECT 0.190 53.200 281.010 53.340 ;
      RECT 0.190 53.760 281.010 53.900 ;
      RECT 0.190 54.320 281.010 54.460 ;
      RECT 0.190 54.880 281.010 55.020 ;
      RECT 0.190 55.440 281.010 55.580 ;
      RECT 0.190 56.000 281.010 56.140 ;
      RECT 0.190 56.560 281.010 56.700 ;
      RECT 0.190 57.120 281.010 57.260 ;
      RECT 0.190 57.680 281.010 57.820 ;
      RECT 0.190 58.240 281.010 58.380 ;
      RECT 0.190 58.800 281.010 58.940 ;
      RECT 0.190 59.360 281.010 59.500 ;
      RECT 0.190 59.920 281.010 60.060 ;
      RECT 0.190 60.480 281.010 60.620 ;
      RECT 0.190 61.040 281.010 61.180 ;
      RECT 0.190 61.600 281.010 61.740 ;
      RECT 0.190 62.160 281.010 62.300 ;
      RECT 0.190 62.720 281.010 62.860 ;
      RECT 0.190 63.280 281.010 63.420 ;
      RECT 0.190 63.840 281.010 63.980 ;
      RECT 0.190 64.400 281.010 64.540 ;
      RECT 0.190 64.960 281.010 65.100 ;
      RECT 0.190 65.520 281.010 65.660 ;
      RECT 0.190 66.080 281.010 66.220 ;
      RECT 0.190 66.640 281.010 66.780 ;
      RECT 0.190 67.200 281.010 67.340 ;
      RECT 0.190 67.760 281.010 67.900 ;
      RECT 0.190 68.320 281.010 68.460 ;
      RECT 0.190 68.880 281.010 69.020 ;
      RECT 0.190 69.440 281.010 69.580 ;
      RECT 0.190 70.000 281.010 70.140 ;
      RECT 0.190 70.560 281.010 70.700 ;
      RECT 0.190 71.120 281.010 71.260 ;
      RECT 0.190 71.680 281.010 71.820 ;
      RECT 0.190 72.240 281.010 72.380 ;
      RECT 0.190 72.800 281.010 72.940 ;
      RECT 0.190 73.360 281.010 73.500 ;
      RECT 0.190 73.920 281.010 74.060 ;
      RECT 0.190 74.480 281.010 74.620 ;
      RECT 0.190 75.040 281.010 75.180 ;
      RECT 0.190 75.600 281.010 75.740 ;
      RECT 0.190 76.160 281.010 76.300 ;
      RECT 0.190 76.720 281.010 76.860 ;
      RECT 0.190 77.280 281.010 77.420 ;
      RECT 0.190 77.840 281.010 77.980 ;
      RECT 0.190 78.400 281.010 78.540 ;
      RECT 0.190 78.960 281.010 79.100 ;
      RECT 0.190 79.520 281.010 79.660 ;
      RECT 0.190 80.080 281.010 80.220 ;
      RECT 0.190 80.640 281.010 80.780 ;
      RECT 0.190 81.200 281.010 81.340 ;
      RECT 0.190 81.760 281.010 81.900 ;
      RECT 0.190 82.320 281.010 82.460 ;
      RECT 0.190 82.880 281.010 83.020 ;
      RECT 0.190 83.440 281.010 83.580 ;
      RECT 0.190 84.000 281.010 84.140 ;
      RECT 0.190 84.560 281.010 84.700 ;
      RECT 0.190 85.120 281.010 85.260 ;
      RECT 0.190 85.680 281.010 85.820 ;
      RECT 0.190 86.240 281.010 86.380 ;
      RECT 0.190 86.800 281.010 86.940 ;
      RECT 0.190 87.360 281.010 87.500 ;
      RECT 0.190 87.920 281.010 88.060 ;
      RECT 0.190 88.480 281.010 88.620 ;
      RECT 0.190 89.040 281.010 89.180 ;
      RECT 0.190 89.600 281.010 89.740 ;
      RECT 0.190 90.160 281.010 90.300 ;
      RECT 0.190 90.720 281.010 90.860 ;
      RECT 0.190 91.280 281.010 91.420 ;
      RECT 0.190 91.840 281.010 91.980 ;
      RECT 0.190 92.400 281.010 92.540 ;
      RECT 0.190 92.960 281.010 93.100 ;
      RECT 0.190 93.520 281.010 93.660 ;
      RECT 0.190 94.080 281.010 94.220 ;
      RECT 0.190 94.640 281.010 94.780 ;
      RECT 0.190 95.200 281.010 95.340 ;
      RECT 0.190 95.760 281.010 95.900 ;
      RECT 0.190 96.320 281.010 96.460 ;
      RECT 0.190 96.880 281.010 97.020 ;
      RECT 0.190 97.440 281.010 97.580 ;
      RECT 0.190 98.000 281.010 98.140 ;
      RECT 0.190 98.560 281.010 98.700 ;
      RECT 0.190 99.120 281.010 99.260 ;
      RECT 0.190 99.680 281.010 99.820 ;
      RECT 0.190 100.240 281.010 100.380 ;
      RECT 0.190 100.800 281.010 100.940 ;
      RECT 0.190 101.360 281.010 101.500 ;
      RECT 0.190 101.920 281.010 102.060 ;
      RECT 0.190 102.480 281.010 102.620 ;
      RECT 0.190 103.040 281.010 103.180 ;
      RECT 0.190 103.600 281.010 103.740 ;
      RECT 0.190 104.160 281.010 104.300 ;
      RECT 0.190 104.720 281.010 104.860 ;
      RECT 0.190 105.280 281.010 105.420 ;
      RECT 0.190 105.840 281.010 105.980 ;
      RECT 0.190 106.400 281.010 106.540 ;
      RECT 0.190 106.960 281.010 107.100 ;
      RECT 0.190 107.520 281.010 107.660 ;
      RECT 0.190 108.080 281.010 108.220 ;
      RECT 0.190 108.640 281.010 108.780 ;
      RECT 0.190 109.200 281.010 109.340 ;
      RECT 0.190 109.760 281.010 109.900 ;
      RECT 0.190 110.320 281.010 110.460 ;
      RECT 0.190 110.880 281.010 111.020 ;
      RECT 0.190 111.440 281.010 111.580 ;
      RECT 0.190 112.000 281.010 112.140 ;
      RECT 0.190 112.560 281.010 112.700 ;
      RECT 0.190 113.120 281.010 113.260 ;
      RECT 0.190 113.680 281.010 113.820 ;
      RECT 0.190 114.240 281.010 114.380 ;
      RECT 0.190 114.800 281.010 114.940 ;
      RECT 0.190 115.360 281.010 115.500 ;
      RECT 0.190 115.920 281.010 116.060 ;
      RECT 0.190 116.480 281.010 116.620 ;
      RECT 0.190 117.040 281.010 117.180 ;
      RECT 0.190 117.600 281.010 117.740 ;
      RECT 0.190 118.160 281.010 118.300 ;
      RECT 0.190 118.720 281.010 118.860 ;
      RECT 0.190 119.280 281.010 119.420 ;
      RECT 0.190 119.840 281.010 119.980 ;
      RECT 0.190 120.400 281.010 120.540 ;
      RECT 0.190 120.960 281.010 121.100 ;
      RECT 0.190 121.520 281.010 121.660 ;
      RECT 0.190 122.080 281.010 122.220 ;
      RECT 0.190 122.640 281.010 122.780 ;
      RECT 0.190 123.200 281.010 123.340 ;
      RECT 0.190 123.760 281.010 123.900 ;
      RECT 0.190 124.320 281.010 124.460 ;
      RECT 0.190 124.880 281.010 125.020 ;
      RECT 0.190 125.440 281.010 125.580 ;
      RECT 0.190 126.000 281.010 126.140 ;
      RECT 0.190 126.560 281.010 126.700 ;
      RECT 0.190 127.120 281.010 127.260 ;
      RECT 0.190 127.680 281.010 127.820 ;
      RECT 0.190 128.240 281.010 128.380 ;
      RECT 0.190 128.800 281.010 128.940 ;
      RECT 0.190 129.360 281.010 129.500 ;
      RECT 0.190 129.920 281.010 130.060 ;
      RECT 0.190 130.480 281.010 130.620 ;
      RECT 0.190 131.040 281.010 131.180 ;
      RECT 0.190 131.600 281.010 131.740 ;
      RECT 0.190 132.160 281.010 132.300 ;
      RECT 0.190 132.720 281.010 132.860 ;
      RECT 0.190 133.280 281.010 133.420 ;
      RECT 0.190 133.840 281.010 133.980 ;
      RECT 0.190 134.400 281.010 134.540 ;
      RECT 0.190 134.960 281.010 135.100 ;
      RECT 0.190 135.520 281.010 135.660 ;
      RECT 0.190 136.080 281.010 136.220 ;
      RECT 0.190 136.640 281.010 136.780 ;
      RECT 0.190 137.200 281.010 137.340 ;
      RECT 0.190 137.760 281.010 137.900 ;
      RECT 0.190 138.320 281.010 138.460 ;
      RECT 0.190 138.880 281.010 139.020 ;
      RECT 0.190 139.440 281.010 139.580 ;
      RECT 0.190 140.000 281.010 140.140 ;
      RECT 0.190 140.560 281.010 140.700 ;
      RECT 0.190 141.120 281.010 141.260 ;
    END
  END VDD
  PIN VSS
    DIRECTION INOUT ;
    USE GROUND ;
    PORT
      LAYER metal4 ;
      RECT 0.190 0.280 281.010 0.420 ;
      RECT 0.190 0.840 281.010 0.980 ;
      RECT 0.190 1.400 281.010 1.540 ;
      RECT 0.190 1.960 281.010 2.100 ;
      RECT 0.190 2.520 281.010 2.660 ;
      RECT 0.190 3.080 281.010 3.220 ;
      RECT 0.190 3.640 281.010 3.780 ;
      RECT 0.190 4.200 281.010 4.340 ;
      RECT 0.190 4.760 281.010 4.900 ;
      RECT 0.190 5.320 281.010 5.460 ;
      RECT 0.190 5.880 281.010 6.020 ;
      RECT 0.190 6.440 281.010 6.580 ;
      RECT 0.190 7.000 281.010 7.140 ;
      RECT 0.190 7.560 281.010 7.700 ;
      RECT 0.190 8.120 281.010 8.260 ;
      RECT 0.190 8.680 281.010 8.820 ;
      RECT 0.190 9.240 281.010 9.380 ;
      RECT 0.190 9.800 281.010 9.940 ;
      RECT 0.190 10.360 281.010 10.500 ;
      RECT 0.190 10.920 281.010 11.060 ;
      RECT 0.190 11.480 281.010 11.620 ;
      RECT 0.190 12.040 281.010 12.180 ;
      RECT 0.190 12.600 281.010 12.740 ;
      RECT 0.190 13.160 281.010 13.300 ;
      RECT 0.190 13.720 281.010 13.860 ;
      RECT 0.190 14.280 281.010 14.420 ;
      RECT 0.190 14.840 281.010 14.980 ;
      RECT 0.190 15.400 281.010 15.540 ;
      RECT 0.190 15.960 281.010 16.100 ;
      RECT 0.190 16.520 281.010 16.660 ;
      RECT 0.190 17.080 281.010 17.220 ;
      RECT 0.190 17.640 281.010 17.780 ;
      RECT 0.190 18.200 281.010 18.340 ;
      RECT 0.190 18.760 281.010 18.900 ;
      RECT 0.190 19.320 281.010 19.460 ;
      RECT 0.190 19.880 281.010 20.020 ;
      RECT 0.190 20.440 281.010 20.580 ;
      RECT 0.190 21.000 281.010 21.140 ;
      RECT 0.190 21.560 281.010 21.700 ;
      RECT 0.190 22.120 281.010 22.260 ;
      RECT 0.190 22.680 281.010 22.820 ;
      RECT 0.190 23.240 281.010 23.380 ;
      RECT 0.190 23.800 281.010 23.940 ;
      RECT 0.190 24.360 281.010 24.500 ;
      RECT 0.190 24.920 281.010 25.060 ;
      RECT 0.190 25.480 281.010 25.620 ;
      RECT 0.190 26.040 281.010 26.180 ;
      RECT 0.190 26.600 281.010 26.740 ;
      RECT 0.190 27.160 281.010 27.300 ;
      RECT 0.190 27.720 281.010 27.860 ;
      RECT 0.190 28.280 281.010 28.420 ;
      RECT 0.190 28.840 281.010 28.980 ;
      RECT 0.190 29.400 281.010 29.540 ;
      RECT 0.190 29.960 281.010 30.100 ;
      RECT 0.190 30.520 281.010 30.660 ;
      RECT 0.190 31.080 281.010 31.220 ;
      RECT 0.190 31.640 281.010 31.780 ;
      RECT 0.190 32.200 281.010 32.340 ;
      RECT 0.190 32.760 281.010 32.900 ;
      RECT 0.190 33.320 281.010 33.460 ;
      RECT 0.190 33.880 281.010 34.020 ;
      RECT 0.190 34.440 281.010 34.580 ;
      RECT 0.190 35.000 281.010 35.140 ;
      RECT 0.190 35.560 281.010 35.700 ;
      RECT 0.190 36.120 281.010 36.260 ;
      RECT 0.190 36.680 281.010 36.820 ;
      RECT 0.190 37.240 281.010 37.380 ;
      RECT 0.190 37.800 281.010 37.940 ;
      RECT 0.190 38.360 281.010 38.500 ;
      RECT 0.190 38.920 281.010 39.060 ;
      RECT 0.190 39.480 281.010 39.620 ;
      RECT 0.190 40.040 281.010 40.180 ;
      RECT 0.190 40.600 281.010 40.740 ;
      RECT 0.190 41.160 281.010 41.300 ;
      RECT 0.190 41.720 281.010 41.860 ;
      RECT 0.190 42.280 281.010 42.420 ;
      RECT 0.190 42.840 281.010 42.980 ;
      RECT 0.190 43.400 281.010 43.540 ;
      RECT 0.190 43.960 281.010 44.100 ;
      RECT 0.190 44.520 281.010 44.660 ;
      RECT 0.190 45.080 281.010 45.220 ;
      RECT 0.190 45.640 281.010 45.780 ;
      RECT 0.190 46.200 281.010 46.340 ;
      RECT 0.190 46.760 281.010 46.900 ;
      RECT 0.190 47.320 281.010 47.460 ;
      RECT 0.190 47.880 281.010 48.020 ;
      RECT 0.190 48.440 281.010 48.580 ;
      RECT 0.190 49.000 281.010 49.140 ;
      RECT 0.190 49.560 281.010 49.700 ;
      RECT 0.190 50.120 281.010 50.260 ;
      RECT 0.190 50.680 281.010 50.820 ;
      RECT 0.190 51.240 281.010 51.380 ;
      RECT 0.190 51.800 281.010 51.940 ;
      RECT 0.190 52.360 281.010 52.500 ;
      RECT 0.190 52.920 281.010 53.060 ;
      RECT 0.190 53.480 281.010 53.620 ;
      RECT 0.190 54.040 281.010 54.180 ;
      RECT 0.190 54.600 281.010 54.740 ;
      RECT 0.190 55.160 281.010 55.300 ;
      RECT 0.190 55.720 281.010 55.860 ;
      RECT 0.190 56.280 281.010 56.420 ;
      RECT 0.190 56.840 281.010 56.980 ;
      RECT 0.190 57.400 281.010 57.540 ;
      RECT 0.190 57.960 281.010 58.100 ;
      RECT 0.190 58.520 281.010 58.660 ;
      RECT 0.190 59.080 281.010 59.220 ;
      RECT 0.190 59.640 281.010 59.780 ;
      RECT 0.190 60.200 281.010 60.340 ;
      RECT 0.190 60.760 281.010 60.900 ;
      RECT 0.190 61.320 281.010 61.460 ;
      RECT 0.190 61.880 281.010 62.020 ;
      RECT 0.190 62.440 281.010 62.580 ;
      RECT 0.190 63.000 281.010 63.140 ;
      RECT 0.190 63.560 281.010 63.700 ;
      RECT 0.190 64.120 281.010 64.260 ;
      RECT 0.190 64.680 281.010 64.820 ;
      RECT 0.190 65.240 281.010 65.380 ;
      RECT 0.190 65.800 281.010 65.940 ;
      RECT 0.190 66.360 281.010 66.500 ;
      RECT 0.190 66.920 281.010 67.060 ;
      RECT 0.190 67.480 281.010 67.620 ;
      RECT 0.190 68.040 281.010 68.180 ;
      RECT 0.190 68.600 281.010 68.740 ;
      RECT 0.190 69.160 281.010 69.300 ;
      RECT 0.190 69.720 281.010 69.860 ;
      RECT 0.190 70.280 281.010 70.420 ;
      RECT 0.190 70.840 281.010 70.980 ;
      RECT 0.190 71.400 281.010 71.540 ;
      RECT 0.190 71.960 281.010 72.100 ;
      RECT 0.190 72.520 281.010 72.660 ;
      RECT 0.190 73.080 281.010 73.220 ;
      RECT 0.190 73.640 281.010 73.780 ;
      RECT 0.190 74.200 281.010 74.340 ;
      RECT 0.190 74.760 281.010 74.900 ;
      RECT 0.190 75.320 281.010 75.460 ;
      RECT 0.190 75.880 281.010 76.020 ;
      RECT 0.190 76.440 281.010 76.580 ;
      RECT 0.190 77.000 281.010 77.140 ;
      RECT 0.190 77.560 281.010 77.700 ;
      RECT 0.190 78.120 281.010 78.260 ;
      RECT 0.190 78.680 281.010 78.820 ;
      RECT 0.190 79.240 281.010 79.380 ;
      RECT 0.190 79.800 281.010 79.940 ;
      RECT 0.190 80.360 281.010 80.500 ;
      RECT 0.190 80.920 281.010 81.060 ;
      RECT 0.190 81.480 281.010 81.620 ;
      RECT 0.190 82.040 281.010 82.180 ;
      RECT 0.190 82.600 281.010 82.740 ;
      RECT 0.190 83.160 281.010 83.300 ;
      RECT 0.190 83.720 281.010 83.860 ;
      RECT 0.190 84.280 281.010 84.420 ;
      RECT 0.190 84.840 281.010 84.980 ;
      RECT 0.190 85.400 281.010 85.540 ;
      RECT 0.190 85.960 281.010 86.100 ;
      RECT 0.190 86.520 281.010 86.660 ;
      RECT 0.190 87.080 281.010 87.220 ;
      RECT 0.190 87.640 281.010 87.780 ;
      RECT 0.190 88.200 281.010 88.340 ;
      RECT 0.190 88.760 281.010 88.900 ;
      RECT 0.190 89.320 281.010 89.460 ;
      RECT 0.190 89.880 281.010 90.020 ;
      RECT 0.190 90.440 281.010 90.580 ;
      RECT 0.190 91.000 281.010 91.140 ;
      RECT 0.190 91.560 281.010 91.700 ;
      RECT 0.190 92.120 281.010 92.260 ;
      RECT 0.190 92.680 281.010 92.820 ;
      RECT 0.190 93.240 281.010 93.380 ;
      RECT 0.190 93.800 281.010 93.940 ;
      RECT 0.190 94.360 281.010 94.500 ;
      RECT 0.190 94.920 281.010 95.060 ;
      RECT 0.190 95.480 281.010 95.620 ;
      RECT 0.190 96.040 281.010 96.180 ;
      RECT 0.190 96.600 281.010 96.740 ;
      RECT 0.190 97.160 281.010 97.300 ;
      RECT 0.190 97.720 281.010 97.860 ;
      RECT 0.190 98.280 281.010 98.420 ;
      RECT 0.190 98.840 281.010 98.980 ;
      RECT 0.190 99.400 281.010 99.540 ;
      RECT 0.190 99.960 281.010 100.100 ;
      RECT 0.190 100.520 281.010 100.660 ;
      RECT 0.190 101.080 281.010 101.220 ;
      RECT 0.190 101.640 281.010 101.780 ;
      RECT 0.190 102.200 281.010 102.340 ;
      RECT 0.190 102.760 281.010 102.900 ;
      RECT 0.190 103.320 281.010 103.460 ;
      RECT 0.190 103.880 281.010 104.020 ;
      RECT 0.190 104.440 281.010 104.580 ;
      RECT 0.190 105.000 281.010 105.140 ;
      RECT 0.190 105.560 281.010 105.700 ;
      RECT 0.190 106.120 281.010 106.260 ;
      RECT 0.190 106.680 281.010 106.820 ;
      RECT 0.190 107.240 281.010 107.380 ;
      RECT 0.190 107.800 281.010 107.940 ;
      RECT 0.190 108.360 281.010 108.500 ;
      RECT 0.190 108.920 281.010 109.060 ;
      RECT 0.190 109.480 281.010 109.620 ;
      RECT 0.190 110.040 281.010 110.180 ;
      RECT 0.190 110.600 281.010 110.740 ;
      RECT 0.190 111.160 281.010 111.300 ;
      RECT 0.190 111.720 281.010 111.860 ;
      RECT 0.190 112.280 281.010 112.420 ;
      RECT 0.190 112.840 281.010 112.980 ;
      RECT 0.190 113.400 281.010 113.540 ;
      RECT 0.190 113.960 281.010 114.100 ;
      RECT 0.190 114.520 281.010 114.660 ;
      RECT 0.190 115.080 281.010 115.220 ;
      RECT 0.190 115.640 281.010 115.780 ;
      RECT 0.190 116.200 281.010 116.340 ;
      RECT 0.190 116.760 281.010 116.900 ;
      RECT 0.190 117.320 281.010 117.460 ;
      RECT 0.190 117.880 281.010 118.020 ;
      RECT 0.190 118.440 281.010 118.580 ;
      RECT 0.190 119.000 281.010 119.140 ;
      RECT 0.190 119.560 281.010 119.700 ;
      RECT 0.190 120.120 281.010 120.260 ;
      RECT 0.190 120.680 281.010 120.820 ;
      RECT 0.190 121.240 281.010 121.380 ;
      RECT 0.190 121.800 281.010 121.940 ;
      RECT 0.190 122.360 281.010 122.500 ;
      RECT 0.190 122.920 281.010 123.060 ;
      RECT 0.190 123.480 281.010 123.620 ;
      RECT 0.190 124.040 281.010 124.180 ;
      RECT 0.190 124.600 281.010 124.740 ;
      RECT 0.190 125.160 281.010 125.300 ;
      RECT 0.190 125.720 281.010 125.860 ;
      RECT 0.190 126.280 281.010 126.420 ;
      RECT 0.190 126.840 281.010 126.980 ;
      RECT 0.190 127.400 281.010 127.540 ;
      RECT 0.190 127.960 281.010 128.100 ;
      RECT 0.190 128.520 281.010 128.660 ;
      RECT 0.190 129.080 281.010 129.220 ;
      RECT 0.190 129.640 281.010 129.780 ;
      RECT 0.190 130.200 281.010 130.340 ;
      RECT 0.190 130.760 281.010 130.900 ;
      RECT 0.190 131.320 281.010 131.460 ;
      RECT 0.190 131.880 281.010 132.020 ;
      RECT 0.190 132.440 281.010 132.580 ;
      RECT 0.190 133.000 281.010 133.140 ;
      RECT 0.190 133.560 281.010 133.700 ;
      RECT 0.190 134.120 281.010 134.260 ;
      RECT 0.190 134.680 281.010 134.820 ;
      RECT 0.190 135.240 281.010 135.380 ;
      RECT 0.190 135.800 281.010 135.940 ;
      RECT 0.190 136.360 281.010 136.500 ;
      RECT 0.190 136.920 281.010 137.060 ;
      RECT 0.190 137.480 281.010 137.620 ;
      RECT 0.190 138.040 281.010 138.180 ;
      RECT 0.190 138.600 281.010 138.740 ;
      RECT 0.190 139.160 281.010 139.300 ;
      RECT 0.190 139.720 281.010 139.860 ;
      RECT 0.190 140.280 281.010 140.420 ;
      RECT 0.190 140.840 281.010 140.980 ;
    END
  END VSS
  OBS
    LAYER metal1 ;
      RECT 0.000 0.000 281.200 141.400 ;
    LAYER metal2 ;
      RECT 0.000 0.000 281.200 141.400 ;
    LAYER metal3 ;
      RECT 0.000 0.000 281.200 141.400 ;
  END
END fakeram_65x160_1r1w
END LIBRARY
